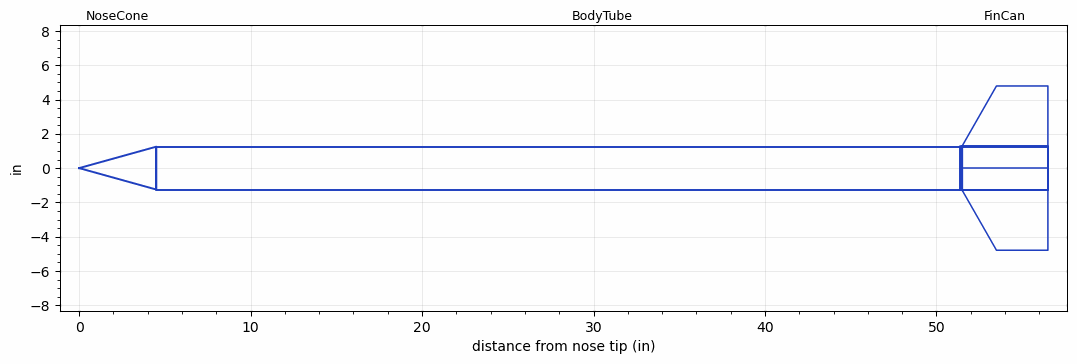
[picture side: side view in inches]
<RASAeroDocument>
 <FileVersion>2</FileVersion>
 <RocketDesign>
  <NoseCone>
   <Length>4.5</Length>
   <Diameter>2.5</Diameter>
   <Shape>Conical</Shape>
   <Location>0</Location>
  </NoseCone>
  <BodyTube>
   <Length>52</Length>
   <Diameter>2.5</Diameter>
   <Location>4.5</Location>
  </BodyTube>
  <FinCan>
   <Length>5</Length>
   <Diameter>2.58</Diameter>
   <InsideDiameter>2.5</InsideDiameter>
   <Location>56.5</Location>
   <ShoulderLength>0.125</ShoulderLength>
   <Offset>-5</Offset>
   <Fin>
    <Count>4</Count>
    <Chord>5</Chord>
    <Span>3.5</Span>
    <SweepDistance>2</SweepDistance>
    <TipChord>3</TipChord>
    <Thickness>0.1875</Thickness>
    <LERadius>0.02</LERadius>
    <Location>5</Location>
    <AirfoilSection>Hexagonal</AirfoilSection>
    <FX1>0.5</FX1>
    <FX3>0.5</FX3>
   </Fin>
  </FinCan>
  <Surface>Camouflage Paint</Surface>
  <ModifiedBarrowman>True</ModifiedBarrowman>
  <Turbulence>True</Turbulence>
  <UseBooster1>False</UseBooster1>
  <UseBooster2>False</UseBooster2>
 </RocketDesign>
 <LaunchSite>
  <Altitude>4000</Altitude>
  <Pressure>0</Pressure>
  <RodAngle>2</RodAngle>
  <RodLength>20</RodLength>
  <Temperature>75</Temperature>
  <WindSpeed>7</WindSpeed>
 </LaunchSite>
 <Recovery>
  <Altitude1>1000</Altitude1>
  <Altitude2>1000</Altitude2>
  <DeviceType1>None</DeviceType1>
  <DeviceType2>None</DeviceType2>
  <Event1>False</Event1>
  <Event2>False</Event2>
  <Size1>1</Size1>
  <Size2>1</Size2>
  <EventType1>None</EventType1>
  <EventType2>None</EventType2>
  <CD1>1.33</CD1>
  <CD2>1.33</CD2>
 </Recovery>
</RASAeroDocument>
